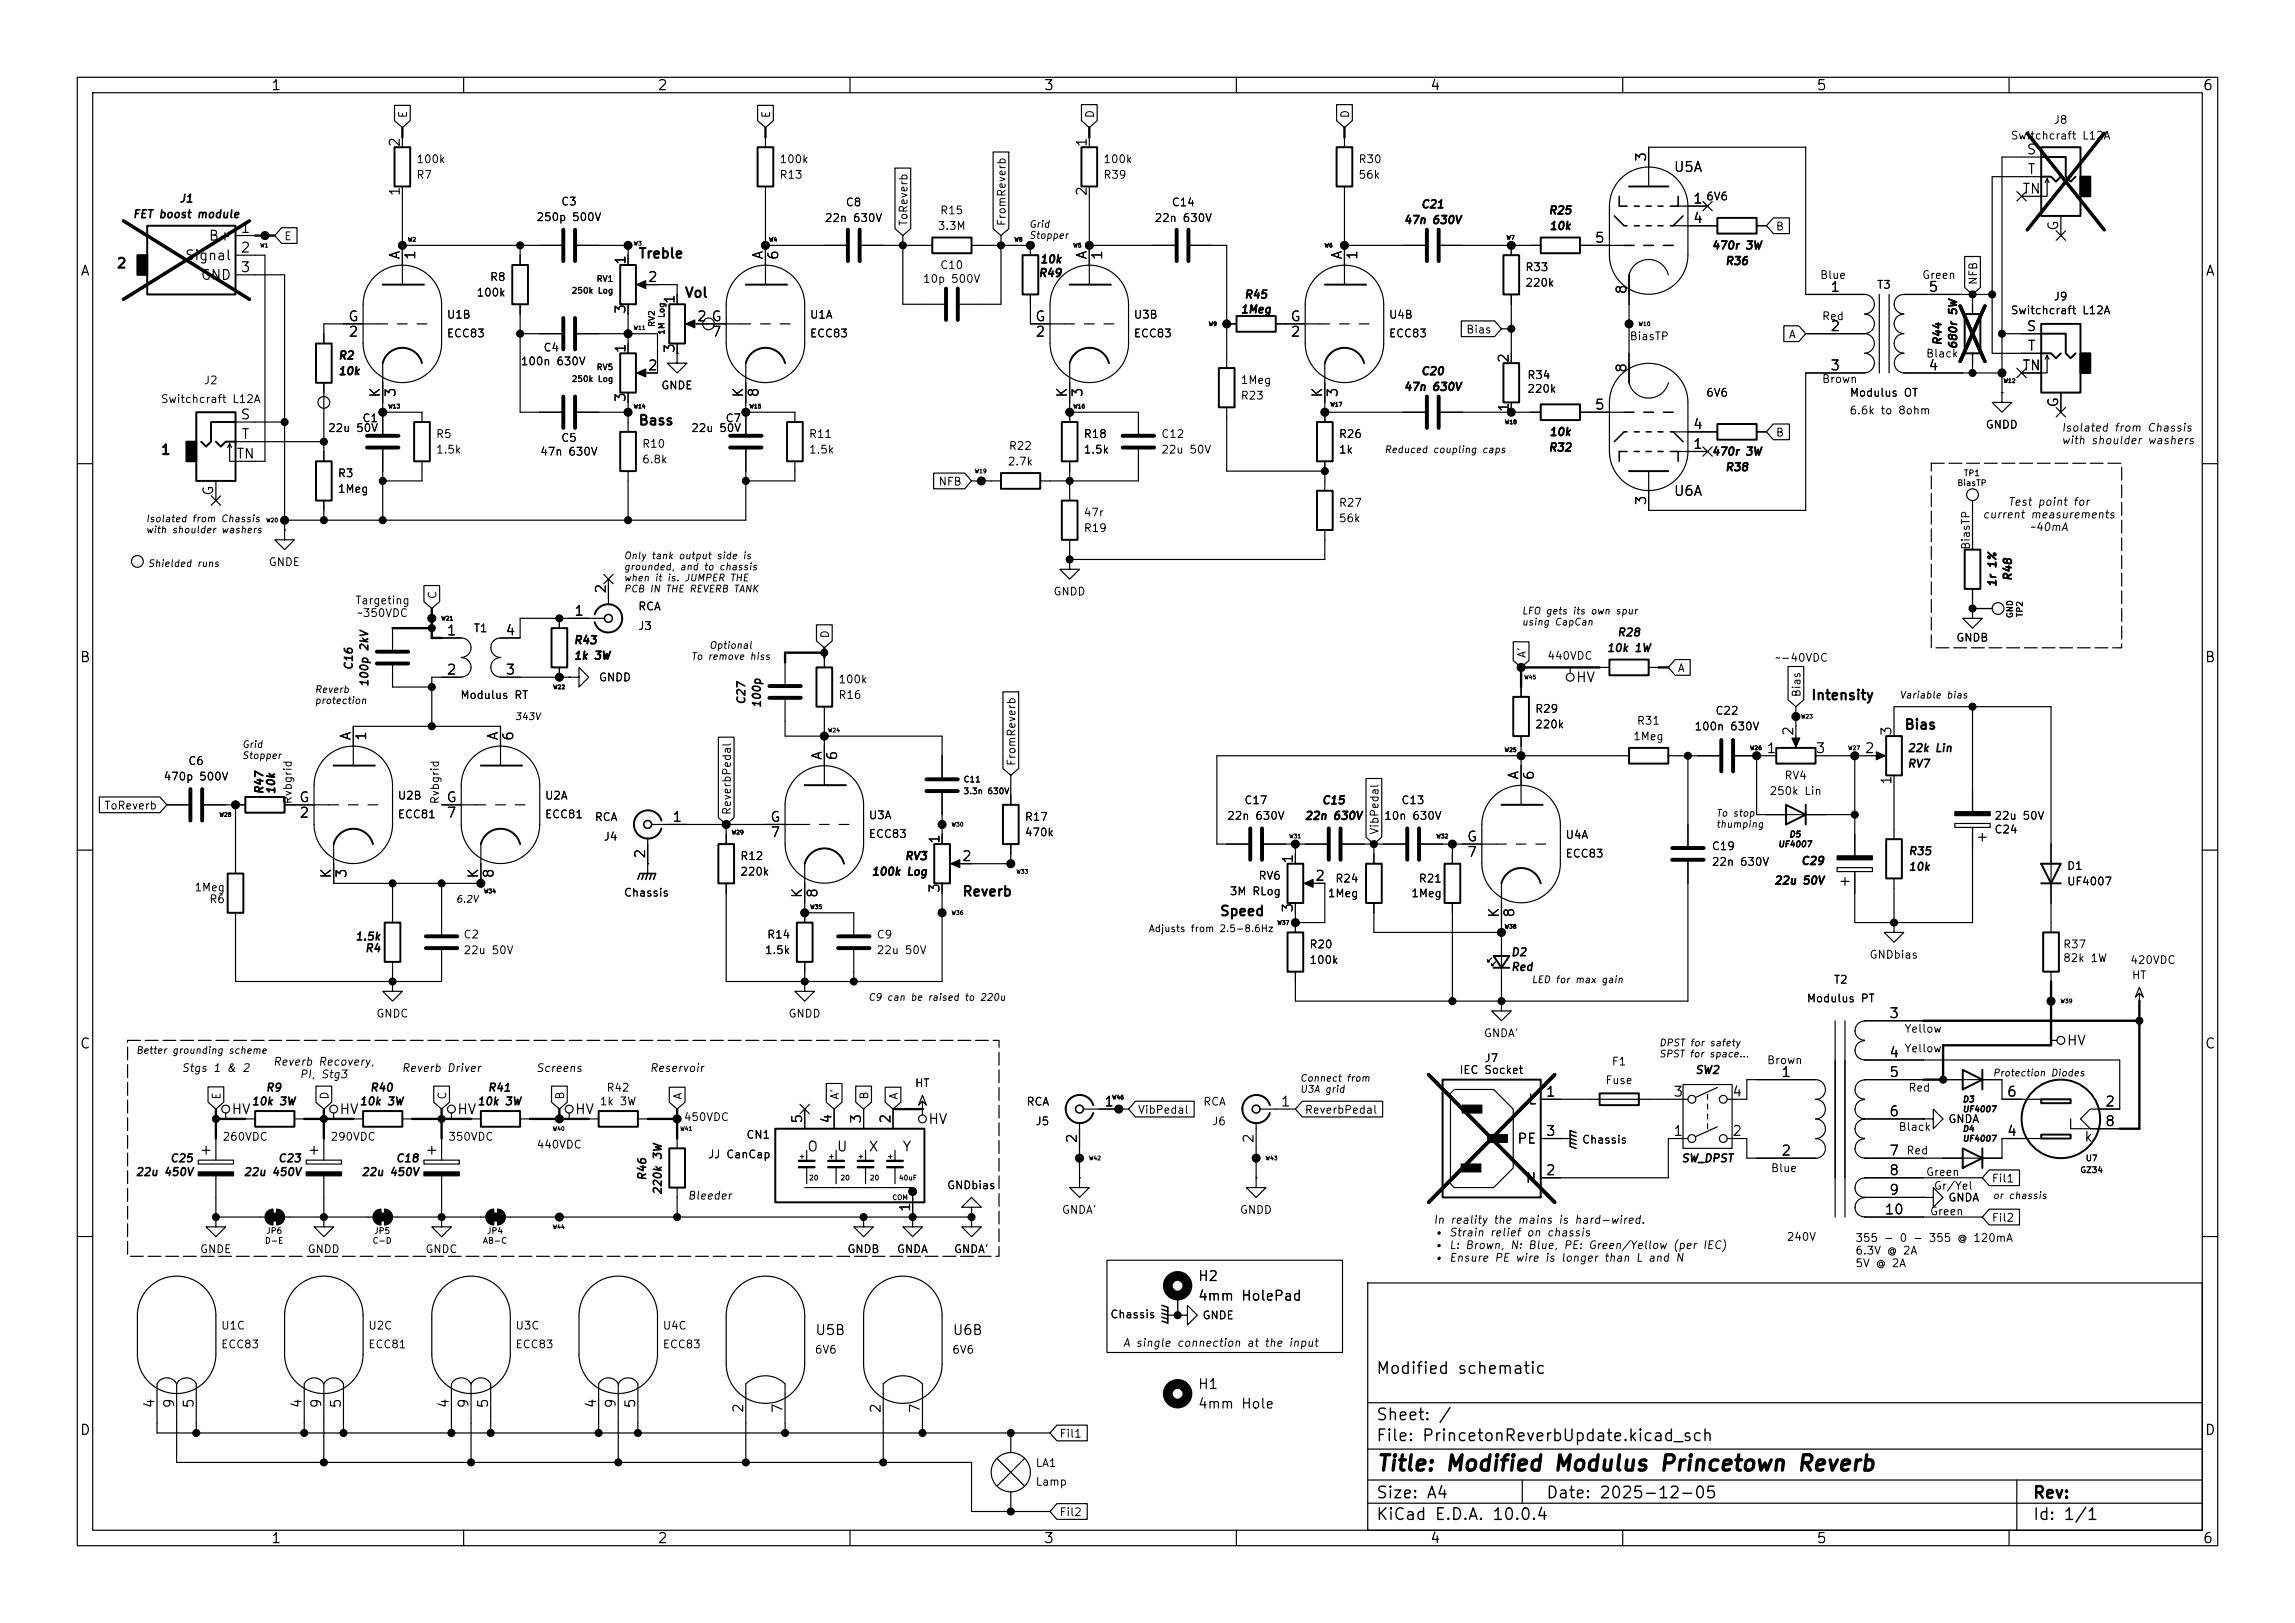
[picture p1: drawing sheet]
<svg xmlns="http://www.w3.org/2000/svg" width="297mm" height="210mm" viewBox="0 0 297 210" stroke-linecap="round" stroke-linejoin="round" font-family="sans-serif">
<defs><g id="words">
<text font-size="2" x="178" y="190.8">Title: Modified Modulus Princetown Reverb</text>
<g font-size="1.5">
<text x="178" y="178.2">Modified schematic</text>
<text x="178" y="184.2">Sheet: /</text>
<text x="178" y="186.9">File: PrincetonReverbUpdate.kicad_sch</text>
<text x="178" y="197.1">KiCad E.D.A. 10.0.4</text>
<text x="178" y="194.3">Size: A4</text>
<text x="200" y="194.3">Date: 2025-12-05</text>
<text x="263" y="194.3">Rev:</text>
<text x="263" y="197.1">Id: 1/1</text>
</g>
<g font-size="1.3">
<text x="35" y="12">1</text>
<text x="85" y="12">2</text>
<text x="135" y="12">3</text>
<text x="185" y="12">4</text>
<text x="235" y="12">5</text>
<text x="285" y="12">6</text>
<text x="52" y="19.1" transform="rotate(-90 52 19.1)">2</text>
<text x="140.9" y="19.1" transform="rotate(-90 140.9 19.1)">1</text>
<text x="213.3" y="21" transform="rotate(-90 213.3 21)">3</text>
<text x="216.5" y="22.6">U5A</text>
<text x="262.2" y="20.3">S</text>
<text x="262.3" y="22.8">T</text>
<text x="52" y="25.5" transform="rotate(-90 52 25.5)">1</text>
<text x="140.9" y="25.5" transform="rotate(-90 140.9 25.5)">2</text>
<text x="219" y="26.6">1</text>
<text x="219" y="29.2">4</text>
<text x="261.6" y="25.4">TN</text>
<text x="266.7" y="29.9" transform="rotate(-90 266.7 29.9)">G</text>
<text x="10.3" y="36">A</text>
<text x="15" y="35">2</text>
<text x="23.8" y="34">Signal</text>
<text x="26.9" y="31.5">B+</text>
<text x="31" y="30.5">1</text>
<text x="31" y="33">2</text>
<text x="31" y="35.5">3</text>
<text x="52" y="33.7" transform="rotate(-90 52 33.7)">A</text>
<text x="54" y="33.7" transform="rotate(-90 54 33.7)">1</text>
<text x="81.3" y="34.4" transform="rotate(-90 81.3 34.4)">1</text>
<text x="82.5" y="33.7">Treble</text>
<text x="99" y="33.7" transform="rotate(-90 99 33.7)">A</text>
<text x="101" y="33.7" transform="rotate(-90 101 33.7)">6</text>
<text x="140.9" y="33.7" transform="rotate(-90 140.9 33.7)">A</text>
<text x="142.9" y="33.7" transform="rotate(-90 142.9 33.7)">1</text>
<text x="174" y="33.7" transform="rotate(-90 174 33.7)">A</text>
<text x="176" y="33.7" transform="rotate(-90 176 33.7)">1</text>
<text x="206.3" y="31.7">5</text>
<text x="285.3" y="36">A</text>
<text x="25.9" y="36.5">GND</text>
<text x="45" y="41.9">G</text>
<text x="81.3" y="40.7" transform="rotate(-90 81.3 40.7)">3</text>
<text x="83.7" y="36.8">2</text>
<text x="87.6" y="39.4" transform="rotate(-90 87.6 39.4)">1</text>
<text x="88.5" y="38.8">Vol</text>
<text x="90.1" y="41.9">2 G</text>
<text x="133.9" y="41.9">G</text>
<text x="166.9" y="41.9">G</text>
<text x="210.8" y="38.2" transform="rotate(-90 210.8 38.2)">8</text>
<text x="236.8" y="38.1">1</text>
<text x="249.5" y="38.1">5</text>
<text x="45" y="43.9">2</text>
<text x="81.3" y="45.8" transform="rotate(-90 81.3 45.8)">1</text>
<text x="87.6" y="45.8" transform="rotate(-90 87.6 45.8)">3</text>
<text x="92" y="43.9">7</text>
<text x="133.9" y="43.9">2</text>
<text x="166.9" y="43.9">2</text>
<text x="195.6" y="47.1" transform="rotate(-90 195.6 47.1)">2</text>
<text x="236.8" y="43.2">2</text>
<text x="262.2" y="43.2">S</text>
<text x="262.3" y="45.7">T</text>
<text x="49.5" y="51.5" transform="rotate(-90 49.5 51.5)">K</text>
<text x="51.5" y="51.5" transform="rotate(-90 51.5 51.5)">3</text>
<text x="81.3" y="52.1" transform="rotate(-90 81.3 52.1)">3</text>
<text x="83.7" y="48.2">2</text>
<text x="96.5" y="51.5" transform="rotate(-90 96.5 51.5)">K</text>
<text x="98.5" y="51.5" transform="rotate(-90 98.5 51.5)">8</text>
<text x="138.4" y="51.5" transform="rotate(-90 138.4 51.5)">K</text>
<text x="140.4" y="51.5" transform="rotate(-90 140.4 51.5)">3</text>
<text x="171.4" y="51.5" transform="rotate(-90 171.4 51.5)">K</text>
<text x="173.4" y="51.5" transform="rotate(-90 173.4 51.5)">3</text>
<text x="195.6" y="53.4" transform="rotate(-90 195.6 53.4)">1</text>
<text x="206.3" y="53.3">5</text>
<text x="210.8" y="48.3" transform="rotate(-90 210.8 48.3)">8</text>
<text x="236.8" y="48.2">3</text>
<text x="249.5" y="48.2">4</text>
<text x="261.6" y="48.2">TN</text>
<text x="266.7" y="52.8" transform="rotate(-90 266.7 52.8)">G</text>
<text x="20.7" y="59.1">1</text>
<text x="30.5" y="59.7">TN</text>
<text x="31" y="54.6">S</text>
<text x="31.2" y="57.1">T</text>
<text x="82.5" y="55.3">Bass</text>
<text x="219" y="58.4">1</text>
<text x="219" y="55.9">4</text>
<text x="27.9" y="64.2" transform="rotate(-90 27.9 64.2)">G</text>
<text x="213.3" y="65.5" transform="rotate(-90 213.3 65.5)">3</text>
<text x="216.5" y="64.5">U6A</text>
<text x="78.7" y="76.9" transform="rotate(-90 78.7 76.9)">2</text>
<text x="57.7" y="82.5">1</text>
<text x="65.3" y="82.5">4</text>
<text x="74.2" y="80">1</text>
<text x="10.3" y="86">B</text>
<text x="57.7" y="87.6">2</text>
<text x="65.3" y="87.6">3</text>
<text x="203.9" y="88.6">HV</text>
<text x="285.3" y="86">B</text>
<text x="45.7" y="95.9" transform="rotate(-90 45.7 95.9)">A</text>
<text x="47.7" y="96" transform="rotate(-90 47.7 96)">1</text>
<text x="64.7" y="95.9" transform="rotate(-90 64.7 95.9)">A</text>
<text x="66.7" y="96" transform="rotate(-90 66.7 96)">6</text>
<text x="232.4" y="95.3" transform="rotate(-90 232.4 95.3)">2</text>
<text x="234.3" y="90.9">Intensity</text>
<text x="245.1" y="95.3" transform="rotate(-90 245.1 95.3)">3</text>
<text x="246.4" y="94.7">Bias</text>
<text x="106.7" y="98.4" transform="rotate(-90 106.7 98.4)">A</text>
<text x="108.6" y="98.5" transform="rotate(-90 108.6 98.5)">6</text>
<text x="196.8" y="101" transform="rotate(-90 196.8 101)">A</text>
<text x="198.8" y="101" transform="rotate(-90 198.8 101)">6</text>
<text x="228.5" y="97.8">1</text>
<text x="234.9" y="97.8">3</text>
<text x="241.2" y="97.8">2</text>
<text x="245.1" y="101.7" transform="rotate(-90 245.1 101.7)">1</text>
<text x="38.6" y="104.1">G</text>
<text x="38.7" y="106.1">2</text>
<text x="57.7" y="104.1">G</text>
<text x="57.7" y="106.1">7</text>
<text x="86.9" y="106.7">1</text>
<text x="99.6" y="106.7">G</text>
<text x="43.2" y="113.8" transform="rotate(-90 43.2 113.8)">K</text>
<text x="45.1" y="113.7" transform="rotate(-90 45.1 113.7)">3</text>
<text x="62.2" y="113.8" transform="rotate(-90 62.2 113.8)">K</text>
<text x="64.2" y="113.7" transform="rotate(-90 64.2 113.7)">8</text>
<text x="83.8" y="111.2" transform="rotate(-90 83.8 111.2)">2</text>
<text x="99.6" y="108.6">7</text>
<text x="121.9" y="109.3" transform="rotate(-90 121.9 109.3)">1</text>
<text x="124.4" y="111.7">2</text>
<text x="167.6" y="111.8" transform="rotate(-90 167.6 111.8)">1</text>
<text x="189.8" y="109.2">G</text>
<text x="189.8" y="111.2">7</text>
<text x="104.1" y="116.3" transform="rotate(-90 104.1 116.3)">K</text>
<text x="106.1" y="116.3" transform="rotate(-90 106.1 116.3)">8</text>
<text x="121.9" y="115.6" transform="rotate(-90 121.9 115.6)">3</text>
<text x="124.5" y="116.3">Reverb</text>
<text x="157.8" y="118.8">Speed</text>
<text x="167.6" y="118.2" transform="rotate(-90 167.6 118.2)">3</text>
<text x="170.1" y="114.3">2</text>
<text x="194.3" y="118.8" transform="rotate(-90 194.3 118.8)">K</text>
<text x="196.3" y="118.8" transform="rotate(-90 196.3 118.8)">8</text>
<text x="10.3" y="136">C</text>
<text x="244.4" y="132.1">3</text>
<text x="244.4" y="137.1">4</text>
<text x="267.4" y="135.6">HV</text>
<text x="285.3" y="136">C</text>
<text x="142.8" y="143.5">1</text>
<text x="165.7" y="143.5">1</text>
<text x="197.7" y="143.2">L</text>
<text x="200" y="142.2">1</text>
<text x="216.5" y="142.2">3</text>
<text x="224.1" y="142.2">4</text>
<text x="230.4" y="139.7">1</text>
<text x="244.4" y="139.7">5</text>
<text x="259.6" y="142.2">6</text>
<text x="272.3" y="143.5">2</text>
<text x="29.9" y="144.5">HV</text>
<text x="43.8" y="144.5">HV</text>
<text x="59.1" y="144.5">HV</text>
<text x="74.3" y="144.5">HV</text>
<text x="104.1" y="145.5" transform="rotate(-90 104.1 145.5)">5</text>
<text x="104.4" y="149.3">O</text>
<text x="107.9" y="145.5" transform="rotate(-90 107.9 145.5)">4</text>
<text x="108.2" y="149.3">U</text>
<text x="111.7" y="145.5" transform="rotate(-90 111.7 145.5)">3</text>
<text x="112.3" y="149.3">X</text>
<text x="115.5" y="145.5" transform="rotate(-90 115.5 145.5)">2</text>
<text x="116.7" y="149.3">Y</text>
<text x="120" y="145.8">HV</text>
<text x="139.7" y="148" transform="rotate(-90 139.7 148)">2</text>
<text x="162.5" y="148" transform="rotate(-90 162.5 148)">2</text>
<text x="196.3" y="148.3">PE</text>
<text x="200" y="147.3">3</text>
<text x="216.5" y="147.3">1</text>
<text x="224.1" y="147.3">2</text>
<text x="230.4" y="149.8">2</text>
<text x="244.4" y="144.8">6</text>
<text x="244.4" y="149.8">7</text>
<text x="259.6" y="147.3">4</text>
<text x="269.6" y="148">k</text>
<text x="272.3" y="146">8</text>
<text x="197.3" y="153.4">N</text>
<text x="200" y="152.4">2</text>
<text x="244.4" y="152.4">8</text>
<text x="244.4" y="154.9">9</text>
<text x="118.1" y="156.9" transform="rotate(-90 118.1 156.9)">1</text>
<text x="243.8" y="157.5">10</text>
<text x="154.9" y="166.1">H2</text>
<text x="105.4" y="173.1">U5B</text>
<text x="123.2" y="173.1">U6B</text>
<text x="154.9" y="168.6">4mm HolePad</text>
<text x="10.3" y="186">D</text>
<text x="20.3" y="182.3" transform="rotate(-90 20.3 182.3)">4</text>
<text x="22.8" y="182.3" transform="rotate(-90 22.8 182.3)">9</text>
<text x="25.4" y="182.3" transform="rotate(-90 25.4 182.3)">5</text>
<text x="39.3" y="182.3" transform="rotate(-90 39.3 182.3)">4</text>
<text x="41.9" y="182.3" transform="rotate(-90 41.9 182.3)">9</text>
<text x="44.4" y="182.3" transform="rotate(-90 44.4 182.3)">5</text>
<text x="58.4" y="182.3" transform="rotate(-90 58.4 182.3)">4</text>
<text x="60.9" y="182.3" transform="rotate(-90 60.9 182.3)">9</text>
<text x="63.5" y="182.3" transform="rotate(-90 63.5 182.3)">5</text>
<text x="77.4" y="182.3" transform="rotate(-90 77.4 182.3)">4</text>
<text x="80" y="182.3" transform="rotate(-90 80 182.3)">9</text>
<text x="82.5" y="182.3" transform="rotate(-90 82.5 182.3)">5</text>
<text x="96.5" y="183" transform="rotate(-90 96.5 183)">2</text>
<text x="101.6" y="183" transform="rotate(-90 101.6 183)">7</text>
<text x="114.3" y="183" transform="rotate(-90 114.3 183)">2</text>
<text x="119.4" y="183" transform="rotate(-90 119.4 183)">7</text>
<text x="154.9" y="180">H1</text>
<text x="154.9" y="182.6">4mm Hole</text>
<text x="285.3" y="186">D</text>
<text x="35" y="200">1</text>
<text x="85" y="200">2</text>
<text x="135" y="200">3</text>
<text x="185" y="200">4</text>
<text x="235" y="200">5</text>
<text x="285" y="200">6</text>
</g>
<g font-size="1">
<text x="52.9" y="15.4" transform="rotate(-90 52.9 15.4)">E</text>
<text x="99.9" y="15.4" transform="rotate(-90 99.9 15.4)">E</text>
<text x="141.8" y="15.4" transform="rotate(-90 141.8 15.4)">D</text>
<text x="174.8" y="15.4" transform="rotate(-90 174.8 15.4)">D</text>
<text x="265.7" y="16.3">J8</text>
<text x="53.8" y="21.4">100k</text>
<text x="53.8" y="23.4">R7</text>
<text x="100.8" y="21.4">100k</text>
<text x="100.8" y="23.4">R13</text>
<text x="142.7" y="21.4">100k</text>
<text x="142.7" y="23.4">R39</text>
<text x="175.7" y="23.4">56k</text>
<text x="175.7" y="21.4">R30</text>
<text x="260.1" y="18.3">Switchcraft L12A</text>
<text x="17.1" y="28.5">FET boost module</text>
<text x="23.1" y="26.5">J1</text>
<text x="69.3" y="28.9">250p 500V</text>
<text x="72.5" y="26.8">C3</text>
<text x="106.7" y="29">22n 630V</text>
<text x="109.4" y="26.9">C8</text>
<text x="117.7" y="29.3" transform="rotate(-90 117.7 29.3)">ToReverb</text>
<text x="121.3" y="30">3.3M</text>
<text x="121.6" y="28">R15</text>
<text x="130.4" y="29.3" transform="rotate(-90 130.4 29.3)">FromReverb</text>
<text x="149.3" y="29">22n 630V</text>
<text x="151.6" y="26.9">C14</text>
<text x="181.6" y="29.2">47n 630V</text>
<text x="183.8" y="27.2">C21</text>
<text x="200.3" y="28">R25</text>
<text x="200.4" y="30">10k</text>
<text x="220.7" y="26.2">6V6</text>
<text x="36.7" y="31.3">E</text>
<text x="121.6" y="35.1">C10</text>
<text x="134.5" y="34.3">10k</text>
<text x="197.3" y="35.3">R33</text>
<text x="221.4" y="32.5">470r 3W</text>
<text x="223.2" y="34.5">R36</text>
<text x="229.7" y="30.1">B</text>
<text x="57.7" y="41.5">U1B</text>
<text x="61.6" y="38.6">100k</text>
<text x="63.3" y="36.6">R8</text>
<text x="104.7" y="41.5">U1A</text>
<text x="119.4" y="36.8">10p 500V</text>
<text x="134.3" y="36.1">R49</text>
<text x="146.6" y="41.5">U3B</text>
<text x="160.5" y="40.8">1Meg</text>
<text x="160.9" y="38.9">R45</text>
<text x="179.7" y="41.5">U4B</text>
<text x="197.3" y="37.3">220k</text>
<text x="235.5" y="36.3">Blue</text>
<text x="235.7" y="41.7">Red</text>
<text x="242.8" y="37.6">T3</text>
<text x="248.7" y="36.3">Green</text>
<text x="256.1" y="37" transform="rotate(-90 256.1 37)">NFB</text>
<text x="260.1" y="40.9">Switchcraft L12A</text>
<text x="265.7" y="39.1">J9</text>
<text x="43.7" y="46.8">R2</text>
<text x="57.7" y="43.9">ECC83</text>
<text x="67.3" y="47.5">100n 630V</text>
<text x="70.3" y="45.7">C4</text>
<text x="104.7" y="43.9">ECC83</text>
<text x="146.6" y="43.9">ECC83</text>
<text x="179.7" y="43.9">ECC83</text>
<text x="189.7" y="43.4">Bias</text>
<text x="210.8" y="44.3">BiasTP</text>
<text x="231.4" y="44">A</text>
<text x="249.2" y="46.5">Black</text>
<text x="251.5" y="44.8" transform="rotate(-90 251.5 44.8)">R44</text>
<text x="253.5" y="45.3" transform="rotate(-90 253.5 45.3)">680r 5W</text>
<text x="20.7" y="52.4">Switchcraft L12A</text>
<text x="26.3" y="50">J2</text>
<text x="43.7" y="48.8">10k</text>
<text x="85.5" y="50.6">GNDE</text>
<text x="160.5" y="52">R23</text>
<text x="160.5" y="49.9">1Meg</text>
<text x="181.6" y="50.8">47n 630V</text>
<text x="183.8" y="48.8">C20</text>
<text x="197.6" y="51.1">220k</text>
<text x="197.6" y="49.3">R34</text>
<text x="220.7" y="51.6">6V6</text>
<text x="235.7" y="49.8">Brown</text>
<text x="239.3" y="53.9">6.6k to 8ohm</text>
<text x="239.3" y="51.6">Modulus OT</text>
<text x="42.4" y="56.1">22u 50V</text>
<text x="46.8" y="54.9">C1</text>
<text x="56.3" y="58.9">1.5k</text>
<text x="56.3" y="56.9">R5</text>
<text x="69.8" y="59.2">47n 630V</text>
<text x="72.5" y="57.4">C5</text>
<text x="83" y="58.2">R10</text>
<text x="89.4" y="56.1">22u 50V</text>
<text x="93.8" y="54.9">C7</text>
<text x="104.6" y="58.9">1.5k</text>
<text x="104.6" y="56.9">R11</text>
<text x="130.5" y="58.5">R22</text>
<text x="140.2" y="58.9">1.5k</text>
<text x="140.2" y="56.9">R18</text>
<text x="150.2" y="56.9">C12</text>
<text x="150.2" y="58.9">22u 50V</text>
<text x="173.2" y="58.9">1k</text>
<text x="173.2" y="56.9">R26</text>
<text x="200.3" y="58.7">R32</text>
<text x="200.4" y="56.6">10k</text>
<text x="221.4" y="59.2">470r 3W</text>
<text x="229.7" y="56.7">B</text>
<text x="256.9" y="55.7">GNDD</text>
<text x="266.7" y="56.1">Isolated from Chassis</text>
<text x="266.7" y="57.7">with shoulder washers</text>
<text x="43.6" y="62">R3</text>
<text x="43.6" y="64">1Meg</text>
<text x="83" y="60.2">6.8k</text>
<text x="121.4" y="63.1">NFB</text>
<text x="130.3" y="60.5">2.7k</text>
<text x="173.2" y="65.8">R27</text>
<text x="223.2" y="61.2">R38</text>
<text x="259.8" y="65.7">Test point for</text>
<text x="140.2" y="69.1">R19</text>
<text x="140.2" y="67.1">47r</text>
<text x="173.2" y="67.8">56k</text>
<text x="255.2" y="71.2" transform="rotate(-90 255.2 71.2)">BiasTP</text>
<text x="256.5" y="67.3">current measurements</text>
<text x="262.6" y="69">~40mA</text>
<text x="34.7" y="73.5">GNDE</text>
<text x="56.7" y="77.6" transform="rotate(-90 56.7 77.6)">C</text>
<text x="136.2" y="77.3">GNDD</text>
<text x="258.6" y="76" transform="rotate(-90 258.6 76)">1r 1%</text>
<text x="260.6" y="75.3" transform="rotate(-90 260.6 75.3)">R48</text>
<text x="45.9" y="78.4">Targeting</text>
<text x="46.1" y="80.1">~350VDC</text>
<text x="61.2" y="82.1">T1</text>
<text x="74.2" y="83.6">R43</text>
<text x="82.5" y="81.8">J3</text>
<text x="82.5" y="79.2">RCA</text>
<text x="107.5" y="82.7" transform="rotate(-90 107.5 82.7)">D</text>
<text x="209.2" y="82.6">R28</text>
<text x="253.1" y="83.3">GNDB</text>
<text x="45.9" y="86.8" transform="rotate(-90 45.9 86.8)">C16</text>
<text x="47.9" y="89" transform="rotate(-90 47.9 89)">100p 2kV</text>
<text x="74.2" y="85.6">1k 3W</text>
<text x="77.4" y="88.4">GNDD</text>
<text x="108.4" y="88.7">100k</text>
<text x="197.7" y="85.2" transform="rotate(-90 197.7 85.2)">A'</text>
<text x="200.2" y="85.6">440VDC</text>
<text x="207.9" y="84.6">10k 1W</text>
<text x="217" y="87.2">A</text>
<text x="229.6" y="85.9">~-40VDC</text>
<text x="59.5" y="90.7">Modulus RT</text>
<text x="96.7" y="91.3" transform="rotate(-90 96.7 91.3)">C27</text>
<text x="98.7" y="91.7" transform="rotate(-90 98.7 91.7)">100p</text>
<text x="108.4" y="90.7">R16</text>
<text x="198.6" y="94.5">220k</text>
<text x="198.6" y="92.5">R29</text>
<text x="211.8" y="94">R31</text>
<text x="219.2" y="94.8">100n 630V</text>
<text x="221.9" y="92.7">C22</text>
<text x="233.3" y="90.3" transform="rotate(-90 233.3 90.3)">Bias</text>
<text x="21.1" y="101.2">470p 500V</text>
<text x="24.3" y="99.2">C6</text>
<text x="131.7" y="99.2" transform="rotate(-90 131.7 99.2)">FromReverb</text>
<text x="211.3" y="96">1Meg</text>
<text x="230.9" y="101.1">RV4</text>
<text x="246.8" y="99.6">RV7</text>
<text x="246.8" y="97.6">22k Lin</text>
<text x="13.4" y="105">ToReverb</text>
<text x="34.3" y="102.9" transform="rotate(-90 34.3 102.9)">R47</text>
<text x="35.8" y="102.9" transform="rotate(-90 35.8 102.9)">10k</text>
<text x="38" y="104.1" transform="rotate(-90 38 104.1)">Rvbgrid</text>
<text x="51.4" y="103.7">U2B</text>
<text x="51.4" y="106.1">ECC81</text>
<text x="57.1" y="104.1" transform="rotate(-90 57.1 104.1)">Rvbgrid</text>
<text x="70.4" y="103.7">U2A</text>
<text x="70.4" y="106.1">ECC81</text>
<text x="76.9" y="106.5">RCA</text>
<text x="94.8" y="105.5" transform="rotate(-90 94.8 105.5)">ReverbPedal</text>
<text x="112.4" y="106.2">U3A</text>
<text x="132.5" y="106.4">R17</text>
<text x="158.7" y="106.3">22n 630V</text>
<text x="161" y="104.3">C17</text>
<text x="168.8" y="106.3">22n 630V</text>
<text x="171" y="104.3">C15</text>
<text x="179.1" y="106.3">10n 630V</text>
<text x="181.3" y="104.3">C13</text>
<text x="228.9" y="103.1">250k Lin</text>
<text x="258" y="106.3">22u 50V</text>
<text x="78.1" y="109">J4</text>
<text x="95.7" y="113.5">220k</text>
<text x="95.7" y="111.5">R12</text>
<text x="112.4" y="108.7">ECC83</text>
<text x="112.7" y="113.5">100k Log</text>
<text x="117" y="111.5">RV3</text>
<text x="132.5" y="108.5">470k</text>
<text x="178.6" y="108.1" transform="rotate(-90 178.6 108.1)">VibPedal</text>
<text x="202.5" y="108.8">U4A</text>
<text x="202.5" y="111.2">ECC83</text>
<text x="221.4" y="110.3">C19</text>
<text x="221.4" y="112.3">22n 630V</text>
<text x="233" y="112.2">C29</text>
<text x="246.9" y="112.9">10k</text>
<text x="246.9" y="110.9">R35</text>
<text x="258" y="108.1">C24</text>
<text x="267.4" y="112.8">D1</text>
<text x="25.1" y="115.6">1Meg</text>
<text x="27" y="117.1">R6</text>
<text x="80.7" y="116.3">Chassis</text>
<text x="159.1" y="116.1">3M RLog</text>
<text x="162.8" y="114.1">RV6</text>
<text x="171.8" y="116.3">1Meg</text>
<text x="172.7" y="114.4">R24</text>
<text x="182.6" y="116.3">1Meg</text>
<text x="183.5" y="114.4">R21</text>
<text x="229.5" y="114.7">22u 50V</text>
<text x="267.4" y="114.8">UF4007</text>
<text x="45.9" y="121.9">1.5k</text>
<text x="47.1" y="123.5">R4</text>
<text x="59.9" y="121.7">C2</text>
<text x="59.9" y="123.7">22u 50V</text>
<text x="98.9" y="123.7">1.5k</text>
<text x="99.2" y="121.7">R14</text>
<text x="113.4" y="121.7">C9</text>
<text x="113.4" y="123.7">22u 50V</text>
<text x="169.4" y="125">100k</text>
<text x="169.4" y="123">R20</text>
<text x="195.5" y="125.9">Red</text>
<text x="195.5" y="124">D2</text>
<text x="241.9" y="124.3">GNDbias</text>
<text x="266.9" y="124.7">82k 1W</text>
<text x="266.9" y="123">R37</text>
<text x="275.6" y="125">420VDC</text>
<text x="48.6" y="131.9">GNDC</text>
<text x="102" y="131.9">GNDD</text>
<text x="233.7" y="129.9">Modulus PT</text>
<text x="237.3" y="127.5">T2</text>
<text x="275.8" y="126.9">HT</text>
<text x="192" y="134.5">GNDA'</text>
<text x="192" y="137.7">J7</text>
<text x="228.6" y="137.9">Brown</text>
<text x="246.4" y="133.9">Yellow</text>
<text x="246.4" y="136.4">Yellow</text>
<text x="23.4" y="139">Stgs 1 &amp; 2</text>
<text x="28.8" y="142.4" transform="rotate(-90 28.8 142.4)">E</text>
<text x="32.5" y="143.3">10k 3W</text>
<text x="34.3" y="141.5">R9</text>
<text x="35.2" y="138.1">Reverb Recovery,</text>
<text x="38.7" y="139.8">PI,</text>
<text x="41.4" y="139.8">Stg3</text>
<text x="42.8" y="142.4" transform="rotate(-90 42.8 142.4)">D</text>
<text x="46.4" y="143.3">10k 3W</text>
<text x="47.8" y="141.5">R40</text>
<text x="51.9" y="139">Reverb Driver</text>
<text x="58" y="142.4" transform="rotate(-90 58 142.4)">C</text>
<text x="61.7" y="143.3">10k 3W</text>
<text x="63" y="141.5">R41</text>
<text x="69.3" y="139">Screens</text>
<text x="73.2" y="142.4" transform="rotate(-90 73.2 142.4)">B</text>
<text x="77.5" y="143.3">1k 3W</text>
<text x="78.4" y="141.5">R42</text>
<text x="84" y="139">Reservoir</text>
<text x="88.5" y="142.4" transform="rotate(-90 88.5 142.4)">A</text>
<text x="108.8" y="142.4" transform="rotate(-90 108.8 142.4)">A'</text>
<text x="112.6" y="142.4" transform="rotate(-90 112.6 142.4)">B</text>
<text x="116.4" y="142.4" transform="rotate(-90 116.4 142.4)">A</text>
<text x="118.3" y="140.9">HT</text>
<text x="132.8" y="143.3">RCA</text>
<text x="155.6" y="143.3">RCA</text>
<text x="188.8" y="139.2">IEC Socket</text>
<text x="207.7" y="140.5">Fuse</text>
<text x="208.5" y="138.1">F1</text>
<text x="219.3" y="139.2">SW2</text>
<text x="246.9" y="141.5">Red</text>
<text x="28.7" y="147.8">260VDC</text>
<text x="42.7" y="147.8">290VDC</text>
<text x="57.9" y="147.8">350VDC</text>
<text x="69.4" y="148.9">440VDC</text>
<text x="88.4" y="145.3">450VDC</text>
<text x="96.5" y="147.6">CN1</text>
<text x="133.9" y="145.9">J5</text>
<text x="147.2" y="144.4">VibPedal</text>
<text x="156.8" y="145.9">J6</text>
<text x="168.8" y="144.4">ReverbPedal</text>
<text x="204.7" y="148.2">Chassis</text>
<text x="245.6" y="146.6">Black</text>
<text x="246.6" y="149.6">Red</text>
<text x="252.1" y="145.6">GNDA</text>
<text x="17.5" y="152.4">22u 450V</text>
<text x="21.9" y="150.6">C25</text>
<text x="31.4" y="152.4">22u 450V</text>
<text x="35.9" y="150.6">C23</text>
<text x="46.7" y="152.4">22u 450V</text>
<text x="51.1" y="150.6">C18</text>
<text x="83.9" y="152.9" transform="rotate(-90 83.9 152.9)">R46</text>
<text x="85.9" y="154.7" transform="rotate(-90 85.9 154.7)">220k 3W</text>
<text x="88.9" y="155.5">Bleeder</text>
<text x="91.6" y="150.1">JJ CanCap</text>
<text x="122.5" y="154.1">GNDbias</text>
<text x="217.5" y="150.6">SW_DPST</text>
<text x="229.1" y="151.9">Blue</text>
<text x="249.2" y="152.4">Green</text>
<text x="250.2" y="154.2">Gr/Yel</text>
<text x="252.1" y="155.7">GNDA</text>
<text x="257.7" y="153.2">Fil1</text>
<text x="137.3" y="157.3">GNDA'</text>
<text x="160.4" y="157.3">GNDD</text>
<text x="185.4" y="158.6">In reality the mains is hard-wired.</text>
<text x="185.4" y="160.2">• Strain relief on chassis</text>
<text x="185.4" y="161.9">• L: Brown,</text>
<text x="195.3" y="161.9">N: Blue,</text>
<text x="202.3" y="161.9">PE: Green/Yellow (per IEC)</text>
<text x="231.1" y="160.8">240V</text>
<text x="240" y="160.9">355 - 0 - 355 @ 120mA</text>
<text x="249.7" y="157.5">Green</text>
<text x="257.7" y="158.3">Fil2</text>
<text x="25.8" y="162.4">GNDE</text>
<text x="39.7" y="162.4">GNDD</text>
<text x="55" y="162.4">GNDC</text>
<text x="109.6" y="162.4">GNDB</text>
<text x="116" y="162.4">GNDA</text>
<text x="123.4" y="162.4">GNDA'</text>
<text x="185.4" y="163.5">• Ensure PE wire is longer than L and N</text>
<text x="240" y="162.6">6.3V @ 2A</text>
<text x="240" y="164.2">5V @ 2A</text>
<text x="28.5" y="172.3">U1C</text>
<text x="47.6" y="172.3">U2C</text>
<text x="66.6" y="172.3">U3C</text>
<text x="85.7" y="172.3">U4C</text>
<text x="143.6" y="170.8">Chassis</text>
<text x="155.5" y="171">GNDE</text>
<text x="28.5" y="174.7">ECC83</text>
<text x="47.6" y="174.7">ECC81</text>
<text x="66.6" y="174.7">ECC83</text>
<text x="85.7" y="174.7">ECC83</text>
<text x="105.4" y="175.4">6V6</text>
<text x="123.2" y="175.4">6V6</text>
<text x="145.2" y="174.5">A single connection at the input</text>
<text x="133.9" y="190.1">LA1</text>
<text x="137" y="186.3">Fil1</text>
<text x="133.9" y="192.5">Lamp</text>
<text x="137" y="196.4">Fil2</text>
</g>
<g font-size=".9">
<text x="133.1" y="29.7">Grid</text>
<text x="133.1" y="31.1">Stopper</text>
<text x="179.1" y="58.9">Reduced coupling caps</text>
<text x="18.8" y="67.8">Isolated from Chassis</text>
<text x="18.8" y="69.2">with shoulder washers</text>
<text x="19" y="73.6">Shielded runs</text>
<text x="80.6" y="72.6">Only tank output side is</text>
<text x="80.6" y="74">grounded,</text>
<text x="80.6" y="75.4">when it is.</text>
<text x="80.6" y="76.9">PCB IN THE REVERB TANK</text>
<text x="87.9" y="74">and to chassis</text>
<text x="88.5" y="75.4">JUMPER THE</text>
<text x="196.8" y="79.7">LFO gets its own spur</text>
<text x="196.8" y="81.2">using CapCan</text>
<text x="40.6" y="89.9">Reverb</text>
<text x="89.4" y="85.6">To remove hiss</text>
<text x="91.7" y="84.2">Optional</text>
<text x="40.6" y="91.3">protection</text>
<text x="66.5" y="93.4">343V</text>
<text x="245.7" y="90.6">Variable bias</text>
<text x="31.2" y="97">Grid</text>
<text x="31.2" y="98.4">Stopper</text>
<text x="222" y="105.9">To stop</text>
<text x="222" y="107.3">thumping</text>
<text x="58.9" y="117">6.2V</text>
<text x="148.6" y="120.8">Adjusts from 2.5-8.6Hz</text>
<text x="112.3" y="129.7">C9 can be raised to 220u</text>
<text x="198.1" y="127.4">LED for max gain</text>
<text x="17.5" y="136.6">Better grounding scheme</text>
<text x="214.6" y="135.6">DPST for safety</text>
<text x="214.6" y="137">SPST for space...</text>
<text x="168.1" y="140.2">Connect from</text>
<text x="168.1" y="141.6">U3A grid</text>
<text x="257.8" y="139.5">Protection Diodes</text>
<text x="257.8" y="155.4">or chassis</text>
</g>
<g font-size=".8">
<text x="73.9" y="38.2">250k Log</text>
<text x="77.1" y="36.7">RV1</text>
<text x="84.9" y="42.4" transform="rotate(-90 84.9 42.4)">RV2</text>
<text x="86.2" y="43.4" transform="rotate(-90 86.2 43.4)">1M Log</text>
<text x="73.9" y="49.6">250k Log</text>
<text x="77.1" y="48.1">RV5</text>
<text x="253.2" y="63.1">BiasTP</text>
<text x="254.1" y="61.8">TP1</text>
<text x="260.7" y="80.1" transform="rotate(-90 260.7 80.1)">GND</text>
<text x="261.9" y="79.9" transform="rotate(-90 261.9 79.9)">TP2</text>
<text x="124.6" y="101.4">C11</text>
<text x="124.6" y="102.9">3.3n 630V</text>
<text x="230" y="109.8">UF4007</text>
<text x="231.5" y="108.5">D5</text>
<text x="253.9" y="142.8">D3</text>
<text x="253.9" y="146.6">D4</text>
<text x="253.9" y="144.1">UF4007</text>
<text x="253.9" y="147.9">UF4007</text>
<text x="269.1" y="152">GZ34</text>
<text x="269.8" y="150.4">U7</text>
<text x="34.2" y="161.1">D-E</text>
<text x="34.4" y="159.8">JP6</text>
<text x="48.1" y="161.1">C-D</text>
<text x="48.3" y="159.8">JP5</text>
<text x="62.4" y="161.1">AB-C</text>
<text x="62.9" y="159.8">JP4</text>
</g>
<g font-size=".6">
<text x="103.3" y="150.1">+</text>
<text x="104.6" y="152.9">20</text>
<text x="107.1" y="150.1">+</text>
<text x="108.7" y="152.9">20</text>
<text x="110.9" y="150.1">+</text>
<text x="112.5" y="152.9">20</text>
<text x="114.8" y="150.1">+</text>
<text x="115.4" y="155.4">COM</text>
<text x="116.3" y="152.9">40uF</text>
</g>
<g font-size=".5">
<text x="33.6" y="32.1">W1</text>
<text x="52.7" y="31.4">W2</text>
<text x="81.9" y="31.9">W3</text>
<text x="99.5" y="31.4">W4</text>
<text x="131.2" y="31.4">W8</text>
<text x="138.8" y="32.1">W5</text>
<text x="171.4" y="32.1">W6</text>
<text x="194.9" y="31.1">W7</text>
<text x="81.9" y="42.8">W11</text>
<text x="156.4" y="42.3">W9</text>
<text x="212" y="42.3">W10</text>
<text x="50.2" y="53">W13</text>
<text x="81.9" y="53">W14</text>
<text x="96.9" y="53">W15</text>
<text x="138.8" y="53">W16</text>
<text x="172.1" y="52.7">W17</text>
<text x="259.2" y="49.7">W12</text>
<text x="194.7" y="55">W18</text>
<text x="126.1" y="61.3">W19</text>
<text x="34.4" y="67.7">W20</text>
<text x="57.1" y="80.4">W21</text>
<text x="71.5" y="89.3">W22</text>
<text x="197.2" y="88">W45</text>
<text x="107.1" y="94.9">W24</text>
<text x="233" y="93.1">W23</text>
<text x="194.7" y="97.4">W25</text>
<text x="226.4" y="97.2">W26</text>
<text x="239.1" y="97.2">W27</text>
<text x="28.4" y="105.8">W28</text>
<text x="123.1" y="107.1">W30</text>
<text x="94.6" y="108.1">W29</text>
<text x="131.5" y="113.2">W33</text>
<text x="166.8" y="108.6">W31</text>
<text x="185.8" y="108.6">W32</text>
<text x="62.6" y="115.7">W34</text>
<text x="104.8" y="117.7">W35</text>
<text x="123.1" y="118.5">W36</text>
<text x="165.3" y="119.8">W37</text>
<text x="194.7" y="120.3">W38</text>
<text x="266.6" y="129.9">W39</text>
<text x="143.9" y="142.4">W46</text>
<text x="71.5" y="146.4">W40</text>
<text x="88" y="146.4">W41</text>
<text x="140.9" y="150.2">W42</text>
<text x="163.7" y="150.2">W43</text>
<text x="71.5" y="159.1">W44</text>
</g>
</g></defs>
<g fill="none" stroke="#000" stroke-width=".15">
<path d="M10 10h277v190h-277zM12 12h273v186h-273zM51.1 13.6h2v2l-1 .9-1-.9zM52.1 17.8v1.3M60 10v2M98 13.6h2.1v2l-1 .9-1.1-.9zM99.1 17.8v1.3M110 10v2M128.5 19.7h2.1v9.9l-1.1 .9-1-.9zM140 13.5h2v2.1l-1 .9-1-.9zM141 17.8v1.3M160 10v2"/>
<path d="M173 13.5h2v2.1l-1 .9-1-.9zM174 17.8v1.3M210 10v2M260 10v2M30.5 33h3.8v26.7h-4.6v-2.3l-.2 .5M30.5 30.5h2.5M30.5 35.6h6.3v33M34.3 30.5h.1M36.4 29.5h2v2h-2l-.8-1zM48.5 35.8a5.1 5.1 0 0 1 5.5-1.1 5.1 5.1 0 0 1 3.1 4.7v5.1a5.1 5.1 0 0 1-5 5 5.1 5.1 0 0 1-5.1-5v-5.1a5.1 5.1 0 0 1 1.5-3.6zM52.1 31.8h.1M52.1 31.8h20.5"/>
<path d="M52.1 24.1v12.7M67.3 31.8v2.5M67.3 39.4v13.9h5.3M74.7 31.8h6.6M81.3 31.8h.1M81.3 31.8v2.5M81.3 39.4v6.3M82.8 36.8h4.8v2.6M95.5 35.8a5.1 5.1 0 0 1 5.5-1.1 5.1 5.1 0 0 1 3.1 4.7v5.1a5.1 5.1 0 0 1-5 5 5.1 5.1 0 0 1-5.1-5v-5.1a5.1 5.1 0 0 1 1.5-3.6zM99.1 31.8h.1M99.1 24.1v12.7M99.1 31.8h10.4"/>
<path d="M111.5 31.8h9.1M115.8 21.8h2.1v7.8l-1.1 .9-1-.9zM116.8 30.5v8.9h5.4M125.7 31.8h7.6M129.5 30.5v8.9h-5.3M133.3 31.8h.1M133.3 38.1v3.8h5.8M133.3 31.8v1.2M137.4 35.8a5.1 5.1 0 0 1 5.5-1.1 5.1 5.1 0 0 1 3.1 4.7v5.1a5.1 5.1 0 0 1-5 5 5.1 5.1 0 0 1-5.1-5v-5.1a5.1 5.1 0 0 1 1.5-3.6zM141 31.8h.1M141 31.8h11M141 24.1v12.7"/>
<path d="M154.1 31.8h4.6v15.8M170.4 35.8a5.1 5.1 0 0 1 5.5-1.1 5.1 5.1 0 0 1 3.2 4.7v5.1a5.1 5.1 0 0 1-5.1 5 5.1 5.1 0 0 1-5.1-5v-5.1a5.1 5.1 0 0 1 1.5-3.6zM174 31.8h.1M174 31.8h10.4M174 24.1v12.7M186.4 31.8h13M195.6 31.8h.1M195.6 31.8v1.2M195.6 38.1v8.9M204.5 31.8h5.7M209.8 23.1a5.1 5.1 0 0 1 5.5-1.1 5.1 5.1 0 0 1 3.1 4.7v6.3a5.1 5.1 0 0 1-5 5.1 5.1 5.1 0 0 1-5.1-5.1v-6.3a5.1 5.1 0 0 1 1.5-3.6zM213.4 24.1v-5h20.3v19h7.6a1.26 1.26 0 0 1 1.3 1.3 1.26 1.26 0 0 1-1.3 1.2 1.27 1.27 0 0 1 1.3 1.3 1.27 1.27 0 0 1-1.3 1.3"/>
<path d="M215.9 35.6a2.62 2.62 0 0 0-2.5-2 2.62 2.62 0 0 0-2.6 2v13.9a2.62 2.62 0 0 0 2.6 2 2.62 2.62 0 0 0 2.5-2M216.5 29.2h5.7M217.2 26.7h3.8M220.4 26.1l1.2 1.2M221.6 26.1l-1.2 1.2M227.3 29.2h1.3M229.5 28.2h2.1v2h-2.1l-.9-1zM243.2 38.1v10.2M244.5 38.1v10.2M254.3 33.2h2v4l-1 .9-1-.9zM255.3 38.1v2.5M257.8 38.1h-11.4a1.25 1.25 0 0 0-1.3 1.3 1.25 1.25 0 0 0 1.3 1.2"/>
<path d="M261 24.8l1.2 1.2M262.2 24.8l-1.2 1.2M264.2 22.9h-6.4v22.8h6.4M264.2 20.3h-5.1v30.5M264.9 23.1l-.2 .5M265.2 23.6l-.3-.5v2.3h-3.3M266.1 29.9l1.2 1.2M266.7 27.9v2.6M267.3 29.9l-1.2 1.2M29.7 57.4l.3 .5M30.5 54.6h6.3M30.5 57.2h11.4"/>
<path d="M41.9 49.5v10.2M49.5 53.3h.1M49.5 47v9.1M49.5 58.2v9.1M49.5 53.3h5.1v1.3M50.2 41.9h-8.3v2.6M51.4 41.9h1.3M54 41.9h1.2M54.6 59.7v2.5h-5.1M67.3 43.2h5.3M74.7 43.2h10.4v5.1h-2.3M74.7 53.3h6.6"/>
<path d="M81.3 43.2h.1M81.3 53.3h.1M81.3 50.8v5.1M87.6 45.7v1.3h1.3l-1.3 1.3-1.2-1.3h1.2M87.6 45.7h.1M87.6 44.5v1.2M89.2 41.9h8M96.5 53.3h.1M96.5 53.3h6.4v1.3M96.5 47v9.1M96.5 58.2v9.1h-59.7M98.4 41.9h1.3"/>
<path d="M101 41.9h1.2M102.9 59.7v2.5h-6.4M138.4 53.3h.1M138.4 47v7.6M138.4 59.7v5.1M138.4 53.3h8.9v2.8M140.3 41.9h1.3M142.9 41.9h1.2M147.3 58.2v4h-12.7M158.7 41.9h.1M158.7 41.9h1.3M158.7 52.7v8.3h12.7"/>
<path d="M165.1 41.9h7M171.4 53.3h.1M171.4 47v7.6M171.4 59.7v3.8M171.4 53.3h13M173.4 41.9h1.2M175.9 41.9h1.3M186.4 53.3h13M189.1 41.5h4.3l.9 1-.9 1.1h-4.3zM194.3 42.5h1.3M195.6 53.3h.1M195.6 52.1v1.2"/>
<path d="M204.5 53.3h5.7M209.8 48.5a5.1 5.1 0 0 1 5.5-1.1 5.1 5.1 0 0 1 3.1 4.7v6.3a5.1 5.1 0 0 1-5 5.1 5.1 5.1 0 0 1-5.1-5.1v-6.3a5.1 5.1 0 0 1 1.5-3.6zM210.8 41.9h.1M216.5 55.9h5.7M217.2 58.4h3.8M220.4 57.8l1.2 1.2M221.6 57.8l-1.2 1.2M227.3 55.9h1.3M229.5 54.9h2.1v2h-2.1l-.9-1zM230.9 42.2h1.9l.9 1-.9 1h-1.9zM233.7 43.2h7.6a1.26 1.26 0 0 1 1.3 1.2 1.26 1.26 0 0 1-1.3 1.3 1.27 1.27 0 0 1 1.3 1.3 1.27 1.27 0 0 1-1.3 1.2M241.3 48.3h-7.6v17.7h-20.3v-5"/>
<path d="M245.2 47a1.24 1.24 0 0 0 1.2 1.2M246.4 40.6a1.25 1.25 0 0 0-1.3 1.3 1.25 1.25 0 0 0 1.3 1.3M246.4 43.2a1.25 1.25 0 0 0-1.3 1.2 1.25 1.25 0 0 0 1.3 1.3M246.4 48.3h12.7M246.4 45.7a1.23 1.23 0 0 0-1.2 1.3M255.3 45.7v2.6M259.1 48.3h.1M259.1 50.8v1.3h1.2l-1.2 1.2-1.3-1.2h1.3M259.1 50.8h.1M259.1 43.2h5.1M261 47.7l1.2 1.2M262.2 47.7l-1.2 1.2"/>
<path d="M264.9 46l-.2 .5M265.2 46.5l-.3-.5v2.3h-3.3M266.1 52.7l1.2 1.2M266.7 50.8v2.5M267.3 52.7l-1.2 1.2M10 60h2M27.3 64.2l1.2 1.2M27.9 62.2v2.6M28.5 64.2l-1.2 1.2M36.8 68.6v1.3h1.3l-1.3 1.2-1.2-1.2h1.2M36.8 68.6h.1M36.8 67.3h.1"/>
<path d="M41.9 64.8v2.5M54.9 75.8h2v2.1l-1 .8-1-.8zM78.1 74.3l1.2 1.2M78.7 74.9v3.3M79.3 74.3l-1.2 1.2M81.3 61v6.3M120.8 61.2h4l.9 1-.9 1h-4zM125.7 62.2h3.8M127 62.2h.1M138.4 72.4v1.3h1.3l-1.3 1.2-1.2-1.2h1.2M138.4 72.4h.1M138.4 69.9v2.5"/>
<path d="M171.4 68.6v3.8h-33M255.3 78.7v1.3h1.2l-1.2 1.3-1.3-1.3h1.3M255.3 78.7h.1M255.3 64.8v6.3M255.3 76.2v2.5M255.3 78.7h2.5M285 60h2M42.1 98a5.1 5.1 0 0 1 5.5-1.1 5.1 5.1 0 0 1 3.2 4.7v5.1a5.1 5.1 0 0 1-5.1 5 5.1 5.1 0 0 1-5.1-5v-5.1a5.1 5.1 0 0 1 1.5-3.6zM45.7 99.1v-5.1h19.1v5.1M50.8 81.3v2.8M50.8 86.1v2.8h5.1M55.9 80h.1"/>
<path d="M57.1 82.6h2.6a1.26 1.26 0 0 1 1.3 1.2 1.26 1.26 0 0 1-1.3 1.3M59.7 85.1a1.26 1.26 0 0 1 1.3 1.3 1.26 1.26 0 0 1-1.3 1.2M59.7 87.6h-3.8v6.4M61.2 98a5.1 5.1 0 0 1 5.5-1.1 5.1 5.1 0 0 1 3.1 4.7v5.1a5.1 5.1 0 0 1-5 5 5.1 5.1 0 0 1-5.1-5v-5.1a5.1 5.1 0 0 1 1.5-3.6zM64.8 85.1a1.25 1.25 0 0 0-1.3 1.2 1.25 1.25 0 0 0 1.3 1.3M64.8 87.6h8.9M72.4 87.6h.1M72.4 80v1.3M72.4 86.4v1.2M73.7 87.6h1.2v-1.2l1.3 1.2-1.3 1.3v-1.3M73.7 87.6h.1M78.2 80h-10.9v2.6h-2.5a1.25 1.25 0 0 0-1.3 1.2 1.25 1.25 0 0 0 1.3 1.3"/>
<path d="M93 95.4h2v10.4l-1 .9-1-.9zM101.6 90.6v4.7h20.3v5.3M101.6 85.7v2.8M105.7 80.8h2v2.1l-1 .9-1-.9zM106.7 95.3h.1M106.7 85.1v1.3M106.7 91.4v10.2M129.8 89.5h2v9.9l-1 .9-1-.9zM195.8 83h2.1v2.5l-1.1 .9-1-.9zM196.8 97.8h.1M196.8 86.4h.1M196.8 88.9v1.3"/>
<path d="M196.8 95.3v8.8M203.2 86.4v.7M207 86.4h1.3M210.8 97.8h-53.3v11.4h4M213.4 86.4h1.2M215.9 97.8h6.6M216.8 85.3h1.9v2.1h-1.9l-.9-1zM218.4 97.8v11.7M224.5 97.8h5.4M227.3 97.8h.1M227.3 97.8v7.6h12.7M231.4 86.2h2v4.4l-1 .8-1-.8z"/>
<path d="M232.4 92.7h.1M232.4 91.4v4.9M234.9 97.8h8.7M240 97.8h.1M240 97.8v12.9M245.1 95.3v-3.9h20.3v29.3M255.3 91.4v13.6M10 110h2M12.9 103.1h7.8l.9 1-.9 1.1h-7.8zM21.6 104.1h2.8M26.4 104.1h5.3M30.5 104.1h.1"/>
<path d="M30.5 118.1v8.9h26.6v-4.1M30.5 104.1v8.9M36.8 104.1h7M43.2 109.2v5.1h19M45.1 104.1h1.3M47.6 104.1h1.3M50.8 114.3v5.1M57.1 114.3v6.6M57.1 104.1h5.8M62.2 114.3h.1M62.2 109.2v5.1M64.1 104.1h1.3"/>
<path d="M66.7 104.1h1.2M83.8 111.8h.1M83.8 108.5v4.5M84.3 106.7h20.5M94 106.7h.1M94 114.3v12.7h27.9v-12.7M94 106.7v2.5M103.1 100.6a5.1 5.1 0 0 1 5.5-1.1 5.1 5.1 0 0 1 3.2 4.6v5.1a5.1 5.1 0 0 1-5.1 5.1 5.1 5.1 0 0 1-5.1-5.1v-5.1a5.1 5.1 0 0 1 1.5-3.5zM104.1 118.1h.1M104.1 111.8v7.6M104.1 118.1h6.4v2.8M106 106.7h1.3"/>
<path d="M108.6 106.7h1.3M121.9 106.7h.1M121.9 118.1h.1M121.9 102.6v6.6M123.4 111.8h7.4M130.8 111.8h.1M130.8 100.3v3.8M130.8 109.2v2.6M163.6 109.2h8.1M167.6 109.2h.1M167.6 119.4h.1M167.6 109.2v2.6"/>
<path d="M167.6 116.8v3.9M169.2 114.3h2.2v5.1h-3.8M173.7 109.2h8.2M176.8 100.7h2v7.6l-1 .9-1-.9zM177.8 109.2v2.6M177.8 116.8v3.9h16.5M183.9 109.2h11M188 109.2h.1M188 109.2v2.6M188 116.8v12.7M193.2 103.1a5.1 5.1 0 0 1 5.6-1.1 5.1 5.1 0 0 1 3.1 4.7v5.1a5.1 5.1 0 0 1-5.1 5 5.1 5.1 0 0 1-5-5v-5.1a5.1 5.1 0 0 1 1.4-3.6zM194.3 114.3v15.2"/>
<path d="M196.2 109.2h1.3M198.8 109.2h1.2M218.4 111.5v18h-50.8v-3.8M237.7 112.3h4.6v.5h-4.6zM238.3 114h1M238.8 113.5v1.1M245.1 119.4v1.3h1.3l-1.3 1.2-1.3-1.2h1.3M245.1 119.4h.1M245.1 100.3v8.3M245.1 113.7v5.7M253 106.6h4.6v.5h-4.6zM255.3 107.1v12.3h-15.3v-6.6"/>
<path d="M256 108.3h1M256.5 107.8v1M285 110h2M50.8 127v1.3h1.3l-1.3 1.2-1.3-1.2h1.3M50.8 127h.1M50.8 124.5v2.5M104.1 127v1.3h1.3l-1.3 1.2-1.2-1.2h1.2M104.1 127h.1M104.1 124.5v2.5M110.5 122.9v4.1M193 124l-.5 .5v-.3v.3h.3M193.5 124.5l-.5 .5v-.3v.3h.3"/>
<path d="M194.3 120.7h.1M194.3 129.5v1.3h1.3l-1.3 1.3-1.3-1.3h1.3M194.3 129.5h.1M237.5 132.1v25.4M238.8 132.1v25.4M240.1 135.9a1.29 1.29 0 0 0 1.2 1.3h33v6.3h-3.8l-1.3 1.3 1.3 1.3h1.3M240.1 133.4a1.24 1.24 0 0 0 1.2 1.2M241.3 139.7h7.6M241.3 132.1h7.6M241.3 132.1a1.23 1.23 0 0 0-1.2 1.3M241.3 134.7a1.23 1.23 0 0 0-1.2 1.2M241.3 139.7a1.23 1.23 0 0 0-1.2 1.3"/>
<path d="M251.5 139.7h7.6v2.5h5.1M265.4 129.5h.1M265.4 125.7v1.3M265.4 134.6h.8M276.9 127.8l.5 1.2-.5-.5-.5 .5zM276.9 128.5v1M276.9 129.5h.1M25.7 150.1h4.5v.5h-4.5zM26.2 148.8h1M26.7 148.3v1.1M26.9 140.6h2.1v2l-1.1 .9-1-.9zM27.9 157.5v1.3h1.3l-1.3 1.2-1.2-1.2h1.2"/>
<path d="M27.9 157.5h.1M27.9 157.5h6.4M27.9 147.3v2.8M27.9 152.1v5.4M29.2 144v.8M31.7 144.8h1.3M35.3 156.5v2M35.8 156.5v2M36.8 157.5h11.5M38.1 144.8h1.3M39.6 150.1h4.6v.5h-4.6zM40.1 148.8h1"/>
<path d="M40.6 148.3v1.1M40.9 140.5h2v2.1l-1 .9-1-.9zM41.9 157.5v1.3h1.3l-1.3 1.2-1.3-1.2h1.3M41.9 157.5h.1M41.9 147.3v2.8M41.9 152.1v5.4M43.2 144v.8M45.7 144.8h1.3M49.3 156.5v2M49.8 156.5v2M50.8 157.5h12.1M52.1 144.8h1.2"/>
<path d="M54.9 150.1h4.5v.5h-4.5zM55.4 148.8h1M55.9 148.3v1.1M56.1 140.5h2.1v2.1l-1.1 .9-1-.9zM57.1 157.5v1.3h1.3l-1.3 1.2-1.2-1.2h1.2M57.1 157.5h.1M57.1 147.3v2.8M57.1 152.1v5.4M58.4 144v.8M61 144.8h1.2M63.9 156.5v2M64.4 156.5v2"/>
<path d="M65.4 157.5h60.3M67.3 144.8h1.3M71.4 140.5h2v2.1l-1 .9-1-.9zM72.4 144.8h.1M72.4 157.5h.1M73.7 144v.8M76.2 144.8h1.3M82.5 144.8h1.3M86.6 140.7h2v1.9l-1 .9-1-.9zM87.6 144.8h.1M87.6 147.3v1.3M87.6 153.7v3.8"/>
<path d="M103.5 142.9l1.2 1.2M104.1 143.5v2.6M104.1 153.7h14M104.4 148.8v1.4M104.4 151v2.2M104.7 142.9l-1.2 1.2M106.9 140.2h2.1v2.4l-1.1 .9-1-.9zM107.9 143.5v2.6M108.2 148.8v1.4M108.2 151v2.2M110.7 140.5h2.1v2.1l-1 .9-1.1-.9zM111.8 157.5v1.3h1.2l-1.2 1.2-1.3-1.2h1.3"/>
<path d="M111.8 157.5h.1M111.8 143.5v2.6M112 148.8v1.4M112 151v2.2M114.6 140.7h2v1.9l-1 .9-1-.9zM115.6 143.5v2.6M115.8 148.8v1.4M115.8 151v2.2M118.1 157.5v1.3h1.3l-1.3 1.2-1.3-1.2h1.3M118.1 157.5h.1M118.1 154.2v3.3M119.4 141.7l.5 1.3-.5-.5-.5 .5z"/>
<path d="M119.4 142.5v1M119.4 143.5h.1M119.4 143.5v.8M125.7 157.5v1.3h1.3l-1.3 1.2-1.2-1.2h1.2M125.7 157.5h.1M125.7 156.2h1.3l-1.3-1.3-1.2 1.3h1.2v1.3M139.7 152.4v1.3h1.3l-1.3 1.2-1.3-1.2h1.3M139.7 152.4h.1M139.7 149.9h.1M139.7 145.3v7.1M140.2 143.5h5.8M144.8 143.5h.1"/>
<path d="M146.9 142.5h7.6v2h-7.6l-.9-1zM162.6 149.9h.1M162.6 152.4v1.3h1.2l-1.2 1.2-1.3-1.2h1.3M162.6 152.4h.1M162.6 145.3v7.1M163.1 143.5h4.5M168.5 142.5h10.4v2h-10.4l-.9-1zM187.7 141.5l.5-.5h5.1l2.5 2.5v7.6l-2.5 2.6h-5.1l-.5-.5zM199.4 142.2h19M199.4 147.3h3.8M201.9 147.3h.1M217.8 140.3h6.4v8.3h-6.4z"/>
<path d="M218.4 147.3h-2.5v5.1h-16.5M221 141.6v.6M221 142.9v.6M221 144.1v.7M221 145.4v.7M222.2 140.7l-2.7 1.3M222.2 145.8l-2.7 1.3M223.5 147.3h2.6v2.6h8.8M234.9 142.2a1.27 1.27 0 0 1 1.3 1.3M234.9 144.8a1.27 1.27 0 0 1 1.3 1.3M234.9 147.3a1.27 1.27 0 0 1 1.3 1.3M236.2 141a1.27 1.27 0 0 0-1.3-1.3h-8.8v2.5h-2.6"/>
<path d="M236.2 141a1.29 1.29 0 0 1-1.2 1.3M236.2 143.6a1.29 1.29 0 0 1-1.2 1.2M236.2 146.1a1.29 1.29 0 0 1-1.2 1.2M236.2 148.6a1.29 1.29 0 0 1-1.2 1.3M240.1 141a1.24 1.24 0 0 0 1.2 1.2M240.1 143.5a1.24 1.24 0 0 0 1.2 1.3M240.1 146.1a1.24 1.24 0 0 0 1.2 1.2M240.1 148.6a1.24 1.24 0 0 0 1.2 1.2M240.1 153.7a1.24 1.24 0 0 0 1.2 1.2M240.1 156.2a1.24 1.24 0 0 0 1.2 1.3M241.3 152.4h15.2M241.3 144.8h7.6"/>
<path d="M241.3 154.9h7.6M241.3 157.5h15.2M241.3 142.3a1.23 1.23 0 0 0-1.2 1.3M241.3 144.8a1.23 1.23 0 0 0-1.2 1.3M241.3 147.4a1.23 1.23 0 0 0-1.2 1.2M241.3 152.4a1.23 1.23 0 0 0-1.2 1.3M241.3 155a1.23 1.23 0 0 0-1.2 1.3M248.9 144.8h1.3v-1.3l1.3 1.3-1.3 1.3v-1.3M248.9 144.8h.1M248.9 154.9h1.3v-1.2l1.3 1.2-1.3 1.3v-1.3M248.9 154.9h.1M257.4 156.5h4v2h-4l-.9-1z"/>
<path d="M257.4 151.4h4v2h-4l-.9-1zM264.2 147.3h-5.1v2.6h-17.8M268 144.8v1.3h3.8M271.8 146.1h2.5M10 160h2M19.3 166.6a5.1 5.1 0 0 1 5.5-1.1 5.1 5.1 0 0 1 3.1 4.7v5.1a5.1 5.1 0 0 1-5 5 5.1 5.1 0 0 1-5.1-5v-5.1a5.1 5.1 0 0 1 1.5-3.6zM22.9 179.1a1.42 1.42 0 0 0-1.3-.8 1.42 1.42 0 0 0-1.3 .8v6.3h115.6M22.9 179.1a1.42 1.42 0 0 1 1.2-.8 1.42 1.42 0 0 1 1.3 .8v6.3M22.9 179.1v10.1h102.8v6.4h10.2M38.3 166.6a5.1 5.1 0 0 1 5.5-1.1 5.1 5.1 0 0 1 3.2 4.7v5.1a5.1 5.1 0 0 1-5.1 5 5.1 5.1 0 0 1-5.1-5v-5.1a5.1 5.1 0 0 1 1.5-3.6zM41.9 179.1a1.42 1.42 0 0 0-1.3-.8 1.42 1.42 0 0 0-1.2 .8v6.3M41.9 179.1a1.42 1.42 0 0 1 1.3-.8 1.42 1.42 0 0 1 1.2 .8v6.3"/>
<path d="M41.9 179.1v10.1M57.4 166.6a5.1 5.1 0 0 1 5.5-1.1 5.1 5.1 0 0 1 3.1 4.7v5.1a5.1 5.1 0 0 1-5 5 5.1 5.1 0 0 1-5.1-5v-5.1a5.1 5.1 0 0 1 1.5-3.6zM61 179.1a1.42 1.42 0 0 0-1.3-.8 1.42 1.42 0 0 0-1.3 .8v6.3M61 179.1a1.42 1.42 0 0 1 1.2-.8 1.42 1.42 0 0 1 1.3 .8v6.3M61 179.1v10.1M76.4 166.6a5.1 5.1 0 0 1 5.5-1.1 5.1 5.1 0 0 1 3.2 4.7v5.1a5.1 5.1 0 0 1-5.1 5 5.1 5.1 0 0 1-5.1-5v-5.1a5.1 5.1 0 0 1 1.5-3.6zM80 179.1a1.42 1.42 0 0 0-1.3-.8 1.42 1.42 0 0 0-1.2 .8v6.3M80 179.1a1.42 1.42 0 0 1 1.3-.8 1.42 1.42 0 0 1 1.2 .8v6.3M80 179.1v10.1M95.5 166.6a5.1 5.1 0 0 1 5.5-1.1 5.1 5.1 0 0 1 3.1 4.7v6.3a5.1 5.1 0 0 1-5 5.1 5.1 5.1 0 0 1-5.1-5.1v-6.3a5.1 5.1 0 0 1 1.5-3.6zM113.2 166.6a5.1 5.1 0 0 1 5.6-1.1 5.1 5.1 0 0 1 3.1 4.7v6.3a5.1 5.1 0 0 1-5.1 5.1 5.1 5.1 0 0 1-5-5.1v-6.3a5.1 5.1 0 0 1 1.4-3.6zM143.3 163.1h30.4v11.9h-30.4z"/>
<path d="M151.1 170.2h1.3M152.4 170.2h1.3v-1.3l1.2 1.3-1.2 1.3v-1.3M152.4 170.2h.1M152.4 167.6v2.6M177 166h108v32h-108zM285 160h2M60 198v2M101.6 185.4v-6.3a3.6 3.6 0 0 0-5.1 0v10.1M110 198v2M119.4 185.4v-6.3a3.6 3.6 0 0 0-5.1 0v10.1M129 188.7l3.6 3.6M130.8 185.4v2.6"/>
<path d="M130.8 193v2.6M132.6 188.7l-3.6 3.6M136.8 194.6h3.9v2h-3.9l-.9-1zM136.8 184.4h3.9v2h-3.9l-.9-1zM160 198v2M177 194.5h108M177 191.5h108M177 187.5h108M177 181.5h108M197 191.5v3M210 198v2M260 198v2"/>
<path d="M261 191.5v6.5"/>
<circle cx="34.3" cy="30.5" r=".51"/>
<circle cx="52.1" cy="31.8" r=".51"/>
<circle cx="81.3" cy="31.8" r=".51"/>
<circle cx="99.1" cy="31.8" r=".51"/>
<circle cx="133.4" cy="31.8" r=".51"/>
<circle cx="141" cy="31.8" r=".51"/>
<circle cx="174" cy="31.8" r=".51"/>
<circle cx="195.6" cy="31.8" r=".51"/>
<circle cx="41.9" cy="52.1" r=".76"/>
<circle cx="49.5" cy="53.3" r=".51"/>
<circle cx="81.3" cy="53.3" r=".51"/>
<circle cx="81.3" cy="43.2" r=".51"/>
<circle cx="91.7" cy="41.9" r=".76"/>
<circle cx="96.5" cy="53.3" r=".51"/>
<circle cx="138.4" cy="53.3" r=".51"/>
<circle cx="158.8" cy="41.9" r=".51"/>
<circle cx="171.5" cy="53.3" r=".51"/>
<circle cx="195.6" cy="53.3" r=".51"/>
<circle cx="210.8" cy="41.9" r=".51"/>
<circle cx="259.1" cy="48.3" r=".51"/>
<circle cx="17.8" cy="72.6" r=".76"/>
<circle cx="36.8" cy="67.3" r=".51"/>
<circle cx="127" cy="62.2" r=".51"/>
<circle cx="255.3" cy="64" r=".76"/>
<circle cx="258.6" cy="78.7" r=".76"/>
<circle cx="55.9" cy="80" r=".51"/>
<circle cx="72.4" cy="87.6" r=".51"/>
<circle cx="106.7" cy="95.3" r=".51"/>
<circle cx="196.9" cy="86.4" r=".51"/>
<circle cx="196.9" cy="97.8" r=".51"/>
<circle cx="203.2" cy="87.6" r=".51"/>
<circle cx="227.3" cy="97.8" r=".51"/>
<circle cx="232.4" cy="92.7" r=".51"/>
<circle cx="240" cy="97.8" r=".51"/>
<circle cx="30.5" cy="104.1" r=".51"/>
<circle cx="62.2" cy="114.3" r=".51"/>
<circle cx="94" cy="106.7" r=".51"/>
<circle cx="104.1" cy="118.1" r=".51"/>
<circle cx="121.9" cy="118.1" r=".51"/>
<circle cx="121.9" cy="106.7" r=".51"/>
<circle cx="130.8" cy="111.8" r=".51"/>
<circle cx="167.6" cy="119.4" r=".51"/>
<circle cx="167.6" cy="109.2" r=".51"/>
<circle cx="188" cy="109.2" r=".51"/>
<circle cx="194.3" cy="120.7" r=".51"/>
<circle cx="265.4" cy="129.5" r=".51"/>
<circle cx="266.7" cy="134.6" r=".51"/>
<circle cx="29.2" cy="143.5" r=".51"/>
<circle cx="43.2" cy="143.5" r=".51"/>
<circle cx="58.4" cy="143.5" r=".51"/>
<circle cx="72.4" cy="157.5" r=".51"/>
<circle cx="72.4" cy="144.8" r=".51"/>
<circle cx="73.7" cy="143.5" r=".51"/>
<circle cx="87.6" cy="144.8" r=".51"/>
<circle cx="119.4" cy="144.8" r=".51"/>
<circle cx="139.7" cy="149.9" r=".51"/>
<circle cx="144.8" cy="143.5" r=".51"/>
<circle cx="162.6" cy="149.9" r=".51"/>
<circle cx="218.9" cy="142.2" r=".51"/>
<circle cx="218.9" cy="147.3" r=".51"/>
<circle cx="223" cy="142.2" r=".51"/>
<circle cx="223" cy="147.3" r=".51"/>
<circle cx="130.8" cy="190.5" r="2.54"/>
</g>
<g fill="none" stroke="#000" stroke-width=".25">
<path d="M51.1 19.1h2v5h-2zM98 19.1h2.1v5h-2.1zM140 19.1h2v5h-2zM173 19.1h2v5h-2zM264.2 19.1h5v8.8h-5zM19 29.2h11.5v8.9h-11.5zM49.5 36.8h5.4M66.3 34.3h2v5.1h-2zM80.3 34.3h2v5.1h-2zM86.6 39.4h2v5.1h-2zM96.5 36.8h5.4M120.6 30.7h5.1v2.1h-5.1z"/>
<path d="M132.3 33h2.1v5.1h-2.1zM138.4 36.8h5.4M171.4 36.8h5.4M194.6 33h2v5.1h-2zM199.4 30.7h5.1v2.1h-5.1zM210.8 24.1h5.1M222.2 28.2h5.1v2h-5.1zM264.2 22.9h1.2l.7 .6 .6-.6M264.2 20.3h3.1v2.6l.7 .6 .6-.6M25.4 53.3h5.1v8.9h-5.1zM27.9 57.2l.7 .6 .6-.6h1.3M30.5 54.6h-3.2v2.6l-.6 .6-.7-.6"/>
<path d="M40.9 59.7h2v5.1h-2zM40.9 44.5h2v5h-2zM49.5 47a2.62 2.62 0 0 1 2.6-2 2.62 2.62 0 0 1 2.5 2M53.6 54.6h2v5.1h-2zM80.3 45.7h2v5.1h-2zM80.3 55.9h2v5.1h-2zM96.5 47a2.62 2.62 0 0 1 2.6-2 2.62 2.62 0 0 1 2.5 2M101.9 54.6h2v5.1h-2zM137.4 54.6h2v5.1h-2zM138.4 47a2.62 2.62 0 0 1 2.6-2 2.62 2.62 0 0 1 2.5 2M157.7 47.6h2.1v5.1h-2.1zM160 40.9h5.1v2h-5.1z"/>
<path d="M170.4 54.6h2.1v5.1h-2.1zM171.4 47a2.62 2.62 0 0 1 2.6-2 2.62 2.62 0 0 1 2.5 2M194.6 47h2v5.1h-2zM199.4 52.3h5.1v2.1h-5.1zM222.2 54.9h5.1v2h-5.1zM254.3 40.6h2v5.1h-2zM264.2 41.9h5v8.9h-5zM264.2 45.7h1.2l.7 .7 .6-.7M264.2 43.2h3.1v2.5l.7 .7 .6-.7M77 79.5a1.81 1.81 0 0 1 2.8-1 1.81 1.81 0 0 1 0 3 1.81 1.81 0 0 1-2.8-1M129.5 61.2h5.1v2h-5.1zM137.4 64.8h2v5.1h-2z"/>
<path d="M170.4 63.5h2.1v5.1h-2.1zM210.8 61h5.1M254.3 71.1h2v5.1h-2zM43.2 99.1h5.3M62.2 99.1h5.4M71.4 81.3h2v5.1h-2zM105.7 86.4h2v5h-2zM195.8 90.2h2.1v5.1h-2.1zM208.3 85.3h5.1v2.1h-5.1zM210.8 96.8h5.1v2h-5.1zM229.9 96.8h5v2h-5zM244.1 95.3h2v5h-2z"/>
<path d="M29.5 113h2v5.1h-2zM31.7 103.1h5.1v2.1h-5.1zM43.2 109.2a2.62 2.62 0 0 1 2.5-2 2.62 2.62 0 0 1 2.6 2M49.8 119.4h2v5.1h-2zM62.2 109.2a2.62 2.62 0 0 1 2.6-2 2.62 2.62 0 0 1 2.5 2M85.6 106.2a1.81 1.81 0 0 0-2.8-1 1.81 1.81 0 0 0 0 3 1.81 1.81 0 0 0 2.8-1M93 109.2h2v5.1h-2zM103.1 119.4h2.1v5.1h-2.1zM104.1 101.6h5.4M104.1 111.8a2.62 2.62 0 0 1 2.6-2 2.62 2.62 0 0 1 2.5 2M120.9 109.2h2v5.1h-2zM129.8 104.1h2v5.1h-2z"/>
<path d="M166.6 111.8h2.1v5h-2.1zM176.8 111.8h2v5h-2zM186.9 111.8h2.1v5h-2.1zM194.3 104.1h5.3M194.3 114.3a2.62 2.62 0 0 1 2.5-2 2.62 2.62 0 0 1 2.6 2M231.1 104.1l2.6 1.3-2.6 1.3zM233.7 104.1v2.6M244.1 108.6h2v5.1h-2zM264.2 111.8h2.5l-1.3 2.5zM264.2 114.3h2.5M166.6 120.7h2.1v5h-2.1zM186.7 139.7h12.7v15.2h-12.7z"/>
<path d="M193.3 123.7h2l-1 1.5zM193.3 125.2h2M254 138.4l2.5 1.3-2.5 1.3zM256.5 138.4v2.6M264.4 120.7h2v5h-2zM33 143.8h5.1v2h-5.1zM47 143.8h5.1v2h-5.1zM62.2 143.8h5.1v2h-5.1zM77.5 143.8h5v2h-5zM86.6 148.6h2v5.1h-2zM100.3 146.1h19.3v9.5h-19.3zM141.5 143a1.81 1.81 0 0 0-2.8-1 1.81 1.81 0 0 0 0 3 1.81 1.81 0 0 0 2.8-1"/>
<path d="M160.8 143.5a1.81 1.81 0 0 0 1.5 1.8 1.81 1.81 0 0 0 2-1.3M164.3 143a1.82 1.82 0 0 0-2-1.3 1.82 1.82 0 0 0-1.5 1.8M207 141.5h5.1v1.5h-5.1zM254 148.6l2.5 1.3-2.5 1.2zM256.5 148.6v2.5M264.2 142.2h3.8v.5h-3.8zM264.2 146.8h3.8v.5h-3.8z"/>
<circle cx="266.7" cy="144.8" r="5.1"/>
</g>
<g fill="none" stroke="#000" stroke-width=".51">
<path d="M72.9 29.7v4.1M74.4 29.7v4.1M109.7 29.7v4.1M111.3 29.7v4.1M122.4 37.3v4.1M124 37.3v4.1M152.3 29.7v4.1M153.8 29.7v4.1M184.7 29.7v4.1M186.2 29.7v4.1M47.5 56.4h4.1M47.5 57.9h4.1"/>
<path d="M72.9 41.1v4.1M72.9 51.3v4.1M74.4 41.1v4.1M74.4 51.3v4.1M94.5 56.4h4.1M94.5 57.9h4.1M145.3 56.4h4.1M145.3 57.9h4.1M184.7 51.3v4.1M186.2 51.3v4.1M48.8 85.9h4M48.8 84.3h4"/>
<path d="M99.6 90.3h4M99.6 88.8h4M222.8 95.8v4M224.3 95.8v4M24.6 102.1v4.1M26.2 102.1v4.1M119.9 100.8h4.1M119.9 102.4h4.1M161.8 107.2v4.1M163.3 107.2v4.1M172 107.2v4.1M173.5 107.2v4.1"/>
<path d="M182.1 107.2v4.1M183.6 107.2v4.1M216.4 109.7h4.1M216.4 111.3h4.1M55.1 121.2h4.1M55.1 122.7h4.1M108.5 121.2h4M108.5 122.7h4"/>
</g>
<g fill="none" stroke="#000" stroke-width=".2">
<path d="M208.9 27.9l1.3 1.3h.4M209.5 25.4v1.3h1.1M210.2 31.8h1.3M211.5 26.7h.6M211.5 29.2h.6M212.7 31.8h1.3M213 26.7h.7M213 29.2h.7M214.6 26.7h.6M214.6 29.2h.6M215.3 31.8h1.2M217.2 25.4v1.3h-1"/>
<path d="M217.8 27.9l-1.3 1.3h-.3M210.2 53.3h1.3M210.6 58.4h-1.1v1.3M210.6 55.9h-.4l-1.3 1.3M211.5 58.4h.6M211.5 55.9h.6M212.7 53.3h1.3M213 58.4h.7M213 55.9h.7M214.6 58.4h.6M214.6 55.9h.6M215.3 53.3h1.2"/>
<path d="M216.2 58.4h1v1.3M216.2 55.9h.3l1.3 1.3M82.5 113.8l.3-.8h2l-.2 .8M83.3 113l-.2 .8M83.8 113l-.2 .8M84.3 113l-.2 .8M203.2 147.8l.8 .3M203.2 147.3l.8 .3M203.2 146.8l.8 .3M204 146.6l-.8-.3v2l.8 .3M150.4 168.9l.7 .3v2l-.7-.3M150.4 169.4l.7 .3"/>
<path d="M150.4 169.9l.7 .3M150.4 170.4l.7 .3"/>
<circle cx="78.7" cy="80" r=".51"/>
<circle cx="83.8" cy="106.7" r=".51"/>
<circle cx="139.7" cy="143.5" r=".51"/>
<circle cx="162.6" cy="143.5" r=".51"/>
</g>
<g fill="#000" stroke="#000" stroke-width=".15">
<path d="M82.4 36.8l1.2-.5v1zM82.4 48.3l1.2-.5v1zM88.8 41.9l1.1-.5v1zM231.9 95.5h1l-.5 1.1zM242.8 97.3l1.2 .5-1.2 .5zM123.1 111.8l1.1-.5v1zM168.8 114.3l1.1-.5v1zM237.7 110.7h4.6v.6h-4.6zM253 105h4.6v.5h-4.6zM25.7 151.6h4.5v.5h-4.5zM34.6 156.8l.4-.3h.3v2a1.02 1.02 0 0 1-.9-.6 1.02 1.02 0 0 1 .2-1.1zM35.8 156.5a1.02 1.02 0 0 1 1 1 1.02 1.02 0 0 1-1 1z"/>
<path d="M35.1 157h1v1h-1zM39.6 151.6h4.6v.5h-4.6zM48.6 156.8l.3-.3h.4v2a1.02 1.02 0 0 1-1-.6 1.02 1.02 0 0 1 .3-1.1zM49.8 156.5a1.02 1.02 0 0 1 1 1 1.02 1.02 0 0 1-1 1zM49 157h1v1h-1zM54.9 151.6h4.5v.5h-4.5zM63.2 156.8l.3-.3h.4v2a1.02 1.02 0 0 1-1-.6 1.02 1.02 0 0 1 .3-1.1zM64.4 156.5a1.02 1.02 0 0 1 1 1 1.02 1.02 0 0 1-1 1zM63.6 157h1v1h-1zM189.1 150.6h2.5v1h-2.5zM189.2 143h2.6v1h-2.6zM192.5 146.8h2.6v1h-2.6z"/>
<circle cx="118.1" cy="154.2" r=".51"/>
</g>
<path d="M262.4 17.2l9.9 12.5M272.3 17.2l-9.9 12.5M16 28.6l16.3 10.1M32.3 28.6l-16.3 10.1M253.7 39.6l3.2 7.2M256.9 39.6l-3.2 7.2M184.9 139.1l16.3 16.5M201.2 139.1l-16.3 16.5" fill="none" stroke="#000" stroke-width=".46"/>
<path d="M17.8 33h1.2v2.6h-1.2zM269.2 22.9h1.3v2.5h-1.3zM24.1 57.2h1.3v2.5h-1.3zM269.2 45.7h1.3v2.6h-1.3z" fill="#000" stroke="#000" stroke-width=".25"/>
<g fill="none" stroke="#000" stroke-width=".3">
<path d="M52.1 16.5v1.3M99.1 16.5v1.3M141 16.5v1.3M174 16.5v1.3M33 30.5h2.6M55.9 78.7v3.9h1.2M50.8 81.3h5.1M106.7 84.5h-5.1v1.2M106.7 83.8v1.3M207 86.4h-10.2v2.5M214.6 86.4h1.3M248.9 132.1h28"/>
<path d="M265.4 127v8.3h-13.9v4.4h-2.6M276.9 129.5v16.6h-2.6M27.9 144.8h3.8M27.9 143.5v3.8M39.4 144.8h6.3M41.9 143.5v3.8M53.3 144.8h7.7M57.1 143.5v3.8M68.6 144.8h7.6M72.4 143.5v1.3M83.8 144.8h3.8M87.6 143.5v3.8"/>
<path d="M103.4 150.2h2M103.4 151h2M107.2 150.2h2M107.2 151h2M111 150.2h2M111 151h2M114.8 150.2h2M114.8 151h2M115.6 143.5h3.8"/>
</g>
<g fill="none" stroke="#000" stroke-width="1.3">
<circle cx="152.4" cy="166.4" r="1.27"/>
<circle cx="152.4" cy="180.3" r="1.27"/>
</g>
<path d="M249.9 59.9h24.7v23.9h-24.7zM16.5 134.6h112.8v28h-112.8z" fill="none" stroke="#000" stroke-width=".15" stroke-dasharray="1.7 .6"/>
<g fill="#000" stroke="#000" stroke-width=".13">
<circle cx="34.3" cy="30.5" r=".46"/>
<circle cx="52.1" cy="31.8" r=".46"/>
<circle cx="67.3" cy="31.8" r=".46"/>
<circle cx="81.3" cy="31.8" r=".46"/>
<circle cx="99.1" cy="31.8" r=".46"/>
<circle cx="116.8" cy="31.8" r=".46"/>
<circle cx="129.5" cy="31.8" r=".46"/>
<circle cx="133.3" cy="31.8" r=".46"/>
<circle cx="141" cy="31.8" r=".46"/>
<circle cx="174" cy="31.8" r=".46"/>
<circle cx="195.6" cy="31.8" r=".46"/>
<circle cx="255.3" cy="38.1" r=".46"/>
<circle cx="257.8" cy="38.1" r=".46"/>
<circle cx="36.8" cy="54.6" r=".46"/>
<circle cx="41.9" cy="57.2" r=".46"/>
<circle cx="49.5" cy="53.3" r=".46"/>
<circle cx="67.3" cy="43.2" r=".46"/>
<circle cx="81.3" cy="43.2" r=".46"/>
<circle cx="81.3" cy="53.3" r=".46"/>
<circle cx="96.5" cy="53.3" r=".46"/>
<circle cx="138.4" cy="53.3" r=".46"/>
<circle cx="158.7" cy="41.9" r=".46"/>
<circle cx="171.4" cy="53.3" r=".46"/>
<circle cx="195.6" cy="42.5" r=".46"/>
<circle cx="195.6" cy="53.3" r=".46"/>
<circle cx="210.8" cy="41.9" r=".46"/>
<circle cx="255.3" cy="48.3" r=".46"/>
<circle cx="259.1" cy="43.2" r=".46"/>
<circle cx="259.1" cy="48.3" r=".46"/>
<circle cx="36.8" cy="67.3" r=".46"/>
<circle cx="41.9" cy="67.3" r=".46"/>
<circle cx="49.5" cy="62.2" r=".46"/>
<circle cx="49.5" cy="67.3" r=".46"/>
<circle cx="81.3" cy="67.3" r=".46"/>
<circle cx="96.5" cy="62.2" r=".46"/>
<circle cx="127" cy="62.2" r=".46"/>
<circle cx="138.4" cy="72.4" r=".46"/>
<circle cx="138.4" cy="62.2" r=".46"/>
<circle cx="171.4" cy="61" r=".46"/>
<circle cx="255.3" cy="78.7" r=".46"/>
<circle cx="55.9" cy="94" r=".46"/>
<circle cx="55.9" cy="88.9" r=".46"/>
<circle cx="55.9" cy="80" r=".46"/>
<circle cx="55.9" cy="81.3" r=".46"/>
<circle cx="72.4" cy="80" r=".46"/>
<circle cx="72.4" cy="87.6" r=".46"/>
<circle cx="106.7" cy="95.3" r=".46"/>
<circle cx="106.7" cy="84.5" r=".46"/>
<circle cx="196.8" cy="97.8" r=".46"/>
<circle cx="196.8" cy="86.4" r=".46"/>
<circle cx="218.4" cy="97.8" r=".46"/>
<circle cx="227.3" cy="97.8" r=".46"/>
<circle cx="232.4" cy="92.7" r=".46"/>
<circle cx="240" cy="97.8" r=".46"/>
<circle cx="255.3" cy="91.4" r=".46"/>
<circle cx="30.5" cy="104.1" r=".46"/>
<circle cx="50.8" cy="114.3" r=".46"/>
<circle cx="57.1" cy="114.3" r=".46"/>
<circle cx="62.2" cy="114.3" r=".46"/>
<circle cx="94" cy="106.7" r=".46"/>
<circle cx="104.1" cy="118.1" r=".46"/>
<circle cx="121.9" cy="118.1" r=".46"/>
<circle cx="121.9" cy="106.7" r=".46"/>
<circle cx="130.8" cy="111.8" r=".46"/>
<circle cx="167.6" cy="109.2" r=".46"/>
<circle cx="167.6" cy="119.4" r=".46"/>
<circle cx="177.8" cy="109.2" r=".46"/>
<circle cx="188" cy="109.2" r=".46"/>
<circle cx="240" cy="105.4" r=".46"/>
<circle cx="245.1" cy="119.4" r=".46"/>
<circle cx="50.8" cy="127" r=".46"/>
<circle cx="104.1" cy="127" r=".46"/>
<circle cx="110.5" cy="127" r=".46"/>
<circle cx="188" cy="129.5" r=".46"/>
<circle cx="194.3" cy="129.5" r=".46"/>
<circle cx="194.3" cy="120.7" r=".46"/>
<circle cx="251.5" cy="139.7" r=".46"/>
<circle cx="265.4" cy="129.5" r=".46"/>
<circle cx="276.9" cy="132.1" r=".46"/>
<circle cx="27.9" cy="157.5" r=".46"/>
<circle cx="27.9" cy="144.8" r=".46"/>
<circle cx="41.9" cy="157.5" r=".46"/>
<circle cx="41.9" cy="144.8" r=".46"/>
<circle cx="57.1" cy="144.8" r=".46"/>
<circle cx="57.1" cy="157.5" r=".46"/>
<circle cx="72.4" cy="157.5" r=".46"/>
<circle cx="72.4" cy="144.8" r=".46"/>
<circle cx="87.6" cy="157.5" r=".46"/>
<circle cx="87.6" cy="144.8" r=".46"/>
<circle cx="111.8" cy="157.5" r=".46"/>
<circle cx="118.1" cy="157.5" r=".46"/>
<circle cx="125.7" cy="157.5" r=".46"/>
<circle cx="139.7" cy="149.9" r=".46"/>
<circle cx="144.8" cy="143.5" r=".46"/>
<circle cx="162.6" cy="149.9" r=".46"/>
<circle cx="152.4" cy="170.2" r=".46"/>
<circle cx="25.4" cy="185.4" r=".46"/>
<circle cx="39.4" cy="185.4" r=".46"/>
<circle cx="41.9" cy="189.2" r=".46"/>
<circle cx="44.4" cy="185.4" r=".46"/>
<circle cx="58.4" cy="185.4" r=".46"/>
<circle cx="61" cy="189.2" r=".46"/>
<circle cx="63.5" cy="185.4" r=".46"/>
<circle cx="77.5" cy="185.4" r=".46"/>
<circle cx="80" cy="189.2" r=".46"/>
<circle cx="82.5" cy="185.4" r=".46"/>
<circle cx="96.5" cy="189.2" r=".46"/>
<circle cx="101.6" cy="185.4" r=".46"/>
<circle cx="114.3" cy="189.2" r=".46"/>
<circle cx="119.4" cy="185.4" r=".46"/>
<circle cx="130.8" cy="195.6" r=".46"/>
<circle cx="130.8" cy="185.4" r=".46"/>
</g>
<use href="#words"/>
</svg>
